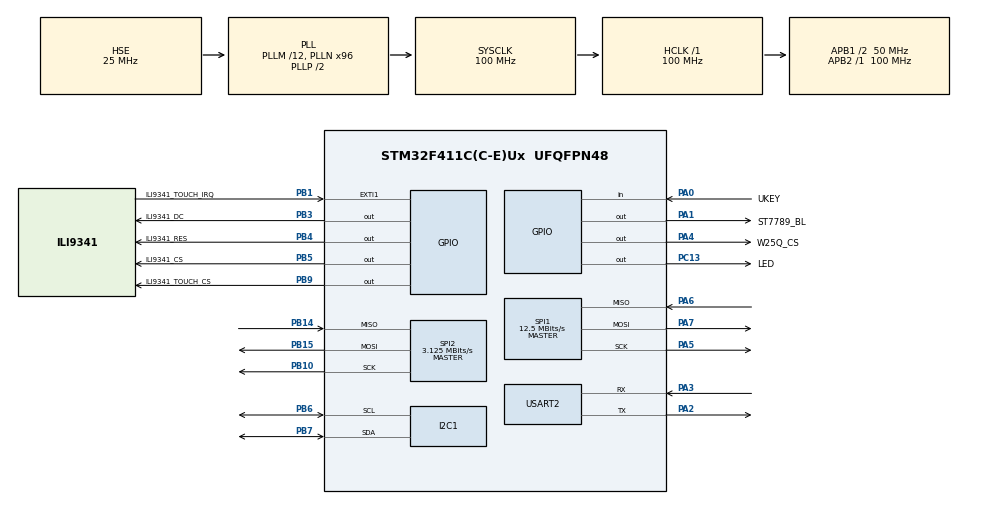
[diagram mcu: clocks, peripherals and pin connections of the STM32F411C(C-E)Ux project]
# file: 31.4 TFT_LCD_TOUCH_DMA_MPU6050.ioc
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Dma.Request0=SPI1_TX
Dma.SPI1_TX.0.Direction=DMA_MEMORY_TO_PERIPH
Dma.SPI1_TX.0.FIFOMode=DMA_FIFOMODE_DISABLE
Dma.SPI1_TX.0.Instance=DMA2_Stream2
Dma.SPI1_TX.0.MemDataAlignment=DMA_MDATAALIGN_BYTE
Dma.SPI1_TX.0.MemInc=DMA_MINC_ENABLE
Dma.SPI1_TX.0.Mode=DMA_NORMAL
Dma.SPI1_TX.0.PeriphDataAlignment=DMA_PDATAALIGN_BYTE
Dma.SPI1_TX.0.PeriphInc=DMA_PINC_DISABLE
Dma.SPI1_TX.0.Priority=DMA_PRIORITY_MEDIUM
Mcu.Family=STM32F4
Mcu.Name=STM32F411C(C-E)Ux
Mcu.Package=UFQFPN48
NVIC.DMA2_Stream2_IRQn=true\:0\:0\:false\:false\:true\:false\:true\:true
NVIC.EXTI1_IRQn=true\:0\:0\:false\:false\:true\:true\:true\:true
NVIC.PriorityGroup=NVIC_PRIORITYGROUP_4
NVIC.SPI1_IRQn=true\:0\:0\:false\:false\:true\:true\:true\:true
NVIC.SPI2_IRQn=true\:0\:0\:false\:false\:true\:true\:true\:true
NVIC.TIM1_UP_TIM10_IRQn=true\:15\:0\:false\:false\:true\:false\:true\:true
NVIC.TIM2_IRQn=true\:1\:0\:true\:false\:true\:true\:true\:true
NVIC.TimeBase=TIM1_UP_TIM10_IRQn
NVIC.TimeBaseIP=TIM10
PA0-WKUP.GPIO_Label=UKEY
PA0-WKUP.GPIO_PuPd=GPIO_PULLUP
PA0-WKUP.Signal=GPIO_Input
PA1.GPIO_Label=ST7789_BL
PA1.Signal=GPIO_Output
PA13.Mode=Serial_Wire
PA13.Signal=SYS_JTMS-SWDIO
PA14.Mode=Serial_Wire
PA14.Signal=SYS_JTCK-SWCLK
PA2.Mode=Asynchronous
PA2.Signal=USART2_TX
PA3.Mode=Asynchronous
PA3.Signal=USART2_RX
PA4.GPIO_Label=W25Q_CS
PA4.Signal=GPIO_Output
PA5.Mode=Full_Duplex_Master
PA5.Signal=SPI1_SCK
PA6.Mode=Full_Duplex_Master
PA6.Signal=SPI1_MISO
PA7.Mode=Full_Duplex_Master
PA7.Signal=SPI1_MOSI
PB1.GPIO_Label=ILI9341_TOUCH_IRQ
PB1.GPIO_ModeDefaultEXTI=GPIO_MODE_IT_FALLING
PB1.GPIO_PuPd=GPIO_PULLUP
PB1.Signal=GPXTI1
PB10.Mode=Full_Duplex_Master
PB10.Signal=SPI2_SCK
PB14.Mode=Full_Duplex_Master
PB14.Signal=SPI2_MISO
PB15.Mode=Full_Duplex_Master
PB15.Signal=SPI2_MOSI
PB3.GPIO_Label=ILI9341_DC
PB3.Signal=GPIO_Output
PB4.GPIO_Label=ILI9341_RES
PB4.Signal=GPIO_Output
PB5.GPIO_Label=ILI9341_CS
PB5.Signal=GPIO_Output
PB6.Mode=I2C
PB6.Signal=I2C1_SCL
PB7.Mode=I2C
PB7.Signal=I2C1_SDA
PB9.GPIO_Label=ILI9341_TOUCH_CS
PB9.Signal=GPIO_Output
PC13-ANTI_TAMP.GPIO_Label=LED
PC13-ANTI_TAMP.Signal=GPIO_Output
PC14-OSC32_IN.Mode=LSE-External-Oscillator
PC14-OSC32_IN.Signal=RCC_OSC32_IN
PC15-OSC32_OUT.Mode=LSE-External-Oscillator
PC15-OSC32_OUT.Signal=RCC_OSC32_OUT
PH0\ -\ OSC_IN.Mode=HSE-External-Oscillator
PH0\ -\ OSC_IN.Signal=RCC_OSC_IN
PH1\ -\ OSC_OUT.Mode=HSE-External-Oscillator
PH1\ -\ OSC_OUT.Signal=RCC_OSC_OUT
ProjectManager.HeapSize=0x400
ProjectManager.StackSize=0x800
ProjectManager.TargetToolchain=STM32CubeIDE
RCC.48MHZClocksFreq_Value=50000000
RCC.AHBFreq_Value=100000000
RCC.APB1CLKDivider=RCC_HCLK_DIV2
RCC.APB1Freq_Value=50000000
RCC.APB1TimFreq_Value=100000000
RCC.APB2Freq_Value=100000000
RCC.APB2TimFreq_Value=100000000
RCC.CortexFreq_Value=100000000
RCC.HCLKFreq_Value=100000000
RCC.HSE_VALUE=25000000
RCC.HSI_VALUE=16000000
RCC.PLLM=12
RCC.PLLN=96
RCC.PLLSourceVirtual=RCC_PLLSOURCE_HSE
RCC.RCC_RTC_Clock_Source=RCC_RTCCLKSOURCE_LSE
RCC.RCC_RTC_Clock_SourceVirtual=RCC_RTCCLKSOURCE_LSE
RCC.SYSCLKFreq_VALUE=100000000
RCC.SYSCLKSource=RCC_SYSCLKSOURCE_PLLCLK
RCC.VCOOutputFreq_Value=200000000
SPI1.BaudRatePrescaler=SPI_BAUDRATEPRESCALER_8
SPI1.CalculateBaudRate=12.5 MBits/s
SPI1.Direction=SPI_DIRECTION_2LINES
SPI1.Mode=SPI_MODE_MASTER
SPI1.VirtualType=VM_MASTER
SPI2.BaudRatePrescaler=SPI_BAUDRATEPRESCALER_16
SPI2.CalculateBaudRate=3.125 MBits/s
SPI2.Direction=SPI_DIRECTION_2LINES
SPI2.Mode=SPI_MODE_MASTER
SPI2.VirtualType=VM_MASTER
TIM2.Period=379
TIM2.Prescaler=8399
USART2.VirtualMode=VM_ASYNC
VP_CRC_VS_CRC.Mode=CRC_Activate
VP_SYS_VS_tim10.Mode=TIM10
VP_TIM2_VS_ClockSourceINT.Mode=Internal
board=custom

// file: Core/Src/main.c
/* USER CODE BEGIN Header */
/**
  ******************************************************************************
  * @file           : main.c
  * @brief          : Main program body
  ******************************************************************************
  * @attention
  *
  * Copyright (c) 2024 STMicroelectronics.
  * All rights reserved.
  *
  * This software is licensed under terms that can be found in the LICENSE file
  * in the root directory of this software component.
  * If no LICENSE file comes with this software, it is provided AS-IS.
  *
  ******************************************************************************
  */
/* USER CODE END Header */
#include "main.h"

/* USER CODE BEGIN Includes */
#include "display_driver.h"
#include "mpu6000.h"
#include "arcade_collection.h"
#include "single_button.h"
#include "w25qxx.h"
/* USER CODE END Includes */

/* USER CODE BEGIN PD */
#define BUTTON_PIN UKEY_Pin
#define BUTTON_PORT UKEY_GPIO_Port
/* USER CODE END PD */

CRC_HandleTypeDef hcrc;
I2C_HandleTypeDef hi2c1;
SPI_HandleTypeDef hspi1;
SPI_HandleTypeDef hspi2;
DMA_HandleTypeDef hdma_spi1_tx;
TIM_HandleTypeDef htim2;
UART_HandleTypeDef huart2;

/* USER CODE BEGIN PV */
ArcadeCollection arcade;
SingleButton ukey_button;
static volatile uint8_t arcade_tick_pending;
/* USER CODE END PV */

void SystemClock_Config(void);
static void MX_GPIO_Init(void);
static void MX_DMA_Init(void);
static void MX_TIM2_Init(void);
static void MX_SPI1_Init(void);
static void MX_CRC_Init(void);
static void MX_SPI2_Init(void);
static void MX_USART2_UART_Init(void);
static void MX_I2C1_Init(void);
/* USER CODE BEGIN PFP */
void init(void);
static uint32_t Arcade_CreateSeed(const MPU6000_Data_t *data);
static void Arcade_ProcessTick(void);
static void Arcade_ProcessButton(void);
/* USER CODE END PFP */

/* USER CODE BEGIN 0 */
static uint32_t Arcade_CreateSeed(const MPU6000_Data_t *data) {
    uint32_t seed = HAL_GetTick() * 0x9E3779B9U;

    seed ^= ((uint32_t)(uint16_t)data->accel_x << 16);
    seed ^= (uint16_t)data->accel_y;
    seed ^= ((uint32_t)(uint16_t)data->accel_z << 1);
    seed ^= ((uint32_t)(uint16_t)data->gyro_x << 11);
    seed ^= ((uint32_t)(uint16_t)data->gyro_y << 21);
    seed ^= ((uint32_t)(uint16_t)data->gyro_z << 5);
    return seed;
}

static void Arcade_ProcessTick(void) {
    MPU6000_Data_t mpu_data;
    HAL_StatusTypeDef mpu_status;

    mpu_status = MPU6000_ReadData(&mpu_data);
    ArcadeCollection_Update(&arcade,
                            &mpu_data,
                            mpu_status);
}

static void Arcade_ProcessButton(void) {
    uint8_t pressed =
        (HAL_GPIO_ReadPin(BUTTON_PORT, BUTTON_PIN) == GPIO_PIN_RESET);
    SingleButtonEvent event =
        SingleButton_Update(&ukey_button, pressed, HAL_GetTick());

    if (event == SINGLE_BUTTON_EVENT_SHORT_PRESS) {
        ArcadeCollection_NextPage(&arcade);
        arcade_tick_pending = 0U;
    } else if (event == SINGLE_BUTTON_EVENT_LONG_PRESS) {
        ArcadeCollection_RestartActive(&arcade);
        arcade_tick_pending = 0U;
    }
}

void init(void) {
    MPU6000_Data_t seed_data;

    DISPLAY_Unselect();
    DISPLAY_TouchUnselect();
    W25Qxx_Unselect();
    DISPLAY_Init();
    MPU6000_Init();
    MPU6000_ReadData(&seed_data);

    SingleButton_Init(
        &ukey_button,
        (HAL_GPIO_ReadPin(BUTTON_PORT, BUTTON_PIN) == GPIO_PIN_RESET),
        HAL_GetTick());
    ArcadeCollection_Init(&arcade, Arcade_CreateSeed(&seed_data));

    arcade_tick_pending = 0U;
    MX_TIM2_Init();
    HAL_TIM_Base_Start_IT(&htim2);
}
/* USER CODE END 0 */

int main(void) {

  /* MCU Configuration--------------------------------------------------------*/
  /* Reset of all peripherals, Initializes the Flash interface and the Systick. */
  HAL_Init();

  /* Configure the system clock */
  SystemClock_Config();

  /* Initialize all configured peripherals */
  MX_GPIO_Init();
  MX_DMA_Init();
  MX_SPI1_Init();
  MX_CRC_Init();
  MX_SPI2_Init();
  MX_USART2_UART_Init();
  MX_I2C1_Init();
  /* USER CODE BEGIN 2 */
  init();
  /* USER CODE END 2 */

  /* Infinite loop */
  /* USER CODE BEGIN WHILE */
  while (1) {
    Arcade_ProcessButton();

    if (arcade_tick_pending != 0U) {
      uint32_t primask = __get_PRIMASK();

      __disable_irq();
      arcade_tick_pending = 0U;
      if (primask == 0U) {
        __enable_irq();
      }

      Arcade_ProcessTick();
    }
    /* USER CODE END WHILE */

  }
}

void SystemClock_Config(void) {
  RCC_OscInitTypeDef RCC_OscInitStruct = {0};
  RCC_ClkInitTypeDef RCC_ClkInitStruct = {0};

  /** Configure the main internal regulator output voltage
  */
  __HAL_RCC_PWR_CLK_ENABLE();
  __HAL_PWR_VOLTAGESCALING_CONFIG(PWR_REGULATOR_VOLTAGE_SCALE1);

  /** Initializes the RCC Oscillators according to the specified parameters
  * in the RCC_OscInitTypeDef structure.
  */
  RCC_OscInitStruct.OscillatorType = RCC_OSCILLATORTYPE_HSE;
  RCC_OscInitStruct.HSEState = RCC_HSE_ON;
  RCC_OscInitStruct.PLL.PLLState = RCC_PLL_ON;
  RCC_OscInitStruct.PLL.PLLSource = RCC_PLLSOURCE_HSE;
  RCC_OscInitStruct.PLL.PLLM = 12;
  RCC_OscInitStruct.PLL.PLLN = 96;
  RCC_OscInitStruct.PLL.PLLP = RCC_PLLP_DIV2;
  RCC_OscInitStruct.PLL.PLLQ = 4;
  if (HAL_RCC_OscConfig(&RCC_OscInitStruct) != HAL_OK) {
    Error_Handler();
  }

  /** Initializes the CPU, AHB and APB buses clocks
  */
  RCC_ClkInitStruct.ClockType = RCC_CLOCKTYPE_HCLK|RCC_CLOCKTYPE_SYSCLK
                              |RCC_CLOCKTYPE_PCLK1|RCC_CLOCKTYPE_PCLK2;
  RCC_ClkInitStruct.SYSCLKSource = RCC_SYSCLKSOURCE_PLLCLK;
  RCC_ClkInitStruct.AHBCLKDivider = RCC_SYSCLK_DIV1;
  RCC_ClkInitStruct.APB1CLKDivider = RCC_HCLK_DIV2;
  RCC_ClkInitStruct.APB2CLKDivider = RCC_HCLK_DIV1;

  if (HAL_RCC_ClockConfig(&RCC_ClkInitStruct, FLASH_LATENCY_3) != HAL_OK) {
    Error_Handler();
  }
}

static void MX_CRC_Init(void) {

  hcrc.Instance = CRC;
  if (HAL_CRC_Init(&hcrc) != HAL_OK) {
    Error_Handler();
  }
}

static void MX_I2C1_Init(void) {

  hi2c1.Instance = I2C1;
  hi2c1.Init.ClockSpeed = 100000;
  hi2c1.Init.DutyCycle = I2C_DUTYCYCLE_2;
  hi2c1.Init.OwnAddress1 = 0;
  hi2c1.Init.AddressingMode = I2C_ADDRESSINGMODE_7BIT;
  hi2c1.Init.DualAddressMode = I2C_DUALADDRESS_DISABLE;
  hi2c1.Init.OwnAddress2 = 0;
  hi2c1.Init.GeneralCallMode = I2C_GENERALCALL_DISABLE;
  hi2c1.Init.NoStretchMode = I2C_NOSTRETCH_DISABLE;
  if (HAL_I2C_Init(&hi2c1) != HAL_OK) {
    Error_Handler();
  }
}

static void MX_SPI1_Init(void) {

  /* SPI1 parameter configuration*/
  hspi1.Instance = SPI1;
  hspi1.Init.Mode = SPI_MODE_MASTER;
  hspi1.Init.Direction = SPI_DIRECTION_2LINES;
  hspi1.Init.DataSize = SPI_DATASIZE_8BIT;
  hspi1.Init.CLKPolarity = SPI_POLARITY_LOW;
  hspi1.Init.CLKPhase = SPI_PHASE_1EDGE;
  hspi1.Init.NSS = SPI_NSS_SOFT;
  hspi1.Init.BaudRatePrescaler = SPI_BAUDRATEPRESCALER_8;
  hspi1.Init.FirstBit = SPI_FIRSTBIT_MSB;
  hspi1.Init.TIMode = SPI_TIMODE_DISABLE;
  hspi1.Init.CRCCalculation = SPI_CRCCALCULATION_DISABLE;
  hspi1.Init.CRCPolynomial = 10;
  if (HAL_SPI_Init(&hspi1) != HAL_OK) {
    Error_Handler();
  }
}

static void MX_SPI2_Init(void) {

  /* SPI2 parameter configuration*/
  hspi2.Instance = SPI2;
  hspi2.Init.Mode = SPI_MODE_MASTER;
  hspi2.Init.Direction = SPI_DIRECTION_2LINES;
  hspi2.Init.DataSize = SPI_DATASIZE_8BIT;
  hspi2.Init.CLKPolarity = SPI_POLARITY_LOW;
  hspi2.Init.CLKPhase = SPI_PHASE_1EDGE;
  hspi2.Init.NSS = SPI_NSS_SOFT;
  hspi2.Init.BaudRatePrescaler = SPI_BAUDRATEPRESCALER_16;
  hspi2.Init.FirstBit = SPI_FIRSTBIT_MSB;
  hspi2.Init.TIMode = SPI_TIMODE_DISABLE;
  hspi2.Init.CRCCalculation = SPI_CRCCALCULATION_DISABLE;
  hspi2.Init.CRCPolynomial = 10;
  if (HAL_SPI_Init(&hspi2) != HAL_OK) {
    Error_Handler();
  }
}

static void MX_TIM2_Init(void) {

  TIM_ClockConfigTypeDef sClockSourceConfig = {0};
  TIM_MasterConfigTypeDef sMasterConfig = {0};

  htim2.Instance = TIM2;
  htim2.Init.Prescaler = 8399;
  htim2.Init.CounterMode = TIM_COUNTERMODE_UP;
  htim2.Init.Period = 380; // 30 Гц (~33 мс)
  htim2.Init.ClockDivision = TIM_CLOCKDIVISION_DIV1;
  htim2.Init.AutoReloadPreload = TIM_AUTORELOAD_PRELOAD_DISABLE;
  if (HAL_TIM_Base_Init(&htim2) != HAL_OK) {
    Error_Handler();
  }
  sClockSourceConfig.ClockSource = TIM_CLOCKSOURCE_INTERNAL;
  if (HAL_TIM_ConfigClockSource(&htim2, &sClockSourceConfig) != HAL_OK) {
    Error_Handler();
  }
  sMasterConfig.MasterOutputTrigger = TIM_TRGO_RESET;
  sMasterConfig.MasterSlaveMode = TIM_MASTERSLAVEMODE_DISABLE;
  if (HAL_TIMEx_MasterConfigSynchronization(&htim2, &sMasterConfig) != HAL_OK) {
    Error_Handler();
  }
  /* USER CODE BEGIN TIM2_Init 2 */
  HAL_NVIC_SetPriority(TIM2_IRQn, 1, 0);
  HAL_NVIC_EnableIRQ(TIM2_IRQn);
  /* USER CODE END TIM2_Init 2 */
}

static void MX_USART2_UART_Init(void) {

  huart2.Instance = USART2;
  huart2.Init.BaudRate = 115200;
  huart2.Init.WordLength = UART_WORDLENGTH_8B;
  huart2.Init.StopBits = UART_STOPBITS_1;
  huart2.Init.Parity = UART_PARITY_NONE;
  huart2.Init.Mode = UART_MODE_TX_RX;
  huart2.Init.HwFlowCtl = UART_HWCONTROL_NONE;
  huart2.Init.OverSampling = UART_OVERSAMPLING_16;
  if (HAL_UART_Init(&huart2) != HAL_OK) {
    Error_Handler();
  }
}

static void MX_DMA_Init(void) {
  /* DMA controller clock enable */
  __HAL_RCC_DMA2_CLK_ENABLE();

  /* DMA interrupt init */
  /* DMA2_Stream2_IRQn interrupt configuration */
  HAL_NVIC_SetPriority(DMA2_Stream2_IRQn, 0, 0);
  HAL_NVIC_EnableIRQ(DMA2_Stream2_IRQn);
}

static void MX_GPIO_Init(void) {
  GPIO_InitTypeDef GPIO_InitStruct = {0};
  /* USER CODE BEGIN MX_GPIO_Init_1 */
  __HAL_RCC_GPIOA_CLK_ENABLE();
  HAL_GPIO_WritePin(W25Q_CS_GPIO_Port,
                    W25Q_CS_Pin,
                    GPIO_PIN_SET);
  /* USER CODE END MX_GPIO_Init_1 */

  /* GPIO Ports Clock Enable */
  __HAL_RCC_GPIOC_CLK_ENABLE();
  __HAL_RCC_GPIOH_CLK_ENABLE();
  __HAL_RCC_GPIOA_CLK_ENABLE();
  __HAL_RCC_GPIOB_CLK_ENABLE();

  /*Configure GPIO pin Output Level */
  HAL_GPIO_WritePin(LED_GPIO_Port, LED_Pin, GPIO_PIN_RESET);

  /*Configure GPIO pin Output Level */
  HAL_GPIO_WritePin(ST7789_BL_GPIO_Port, ST7789_BL_Pin, ST7789_BL_OFF_STATE);

  /*Configure GPIO pin Output Level */
  HAL_GPIO_WritePin(DISPLAY_DC_GPIO_Port, DISPLAY_DC_Pin, GPIO_PIN_RESET);
  HAL_GPIO_WritePin(DISPLAY_RES_GPIO_Port, DISPLAY_RES_Pin, GPIO_PIN_RESET);

  /*Configure GPIO pin Output Level */
  HAL_GPIO_WritePin(DISPLAY_CS_GPIO_Port, DISPLAY_CS_Pin, GPIO_PIN_SET);
  HAL_GPIO_WritePin(DISPLAY_TOUCH_CS_GPIO_Port, DISPLAY_TOUCH_CS_Pin, GPIO_PIN_SET);

  /*Configure GPIO pin : LED_Pin */
  GPIO_InitStruct.Pin = LED_Pin;
  GPIO_InitStruct.Mode = GPIO_MODE_OUTPUT_PP;
  GPIO_InitStruct.Pull = GPIO_NOPULL;
  GPIO_InitStruct.Speed = GPIO_SPEED_FREQ_LOW;
  HAL_GPIO_Init(LED_GPIO_Port, &GPIO_InitStruct);

  /*Configure GPIO pin : UKEY_Pin */
  GPIO_InitStruct.Pin = UKEY_Pin;
  GPIO_InitStruct.Mode = GPIO_MODE_INPUT;
  GPIO_InitStruct.Pull = GPIO_PULLUP;
  HAL_GPIO_Init(UKEY_GPIO_Port, &GPIO_InitStruct);

  /*Configure GPIO pin : ST7789_BL_Pin */
  GPIO_InitStruct.Pin = ST7789_BL_Pin;
  GPIO_InitStruct.Mode = GPIO_MODE_OUTPUT_PP;
  GPIO_InitStruct.Pull = GPIO_NOPULL;
  GPIO_InitStruct.Speed = GPIO_SPEED_FREQ_LOW;
  HAL_GPIO_Init(ST7789_BL_GPIO_Port, &GPIO_InitStruct);

  /*Configure GPIO pin : DISPLAY_TOUCH_IRQ_Pin */
  GPIO_InitStruct.Pin = DISPLAY_TOUCH_IRQ_Pin;
  GPIO_InitStruct.Mode = GPIO_MODE_IT_FALLING;
  GPIO_InitStruct.Pull = GPIO_PULLUP;
  HAL_GPIO_Init(DISPLAY_TOUCH_IRQ_GPIO_Port, &GPIO_InitStruct);

  /*Configure GPIO pins : DISPLAY_DC_Pin DISPLAY_RES_Pin DISPLAY_CS_Pin DISPLAY_TOUCH_CS_Pin */
  GPIO_InitStruct.Mode = GPIO_MODE_OUTPUT_PP;
  GPIO_InitStruct.Pull = GPIO_NOPULL;
  GPIO_InitStruct.Speed = GPIO_SPEED_FREQ_LOW;
  GPIO_InitStruct.Pin = DISPLAY_DC_Pin;
  HAL_GPIO_Init(DISPLAY_DC_GPIO_Port, &GPIO_InitStruct);
  GPIO_InitStruct.Pin = DISPLAY_RES_Pin;
  HAL_GPIO_Init(DISPLAY_RES_GPIO_Port, &GPIO_InitStruct);
  GPIO_InitStruct.Pin = DISPLAY_CS_Pin;
  HAL_GPIO_Init(DISPLAY_CS_GPIO_Port, &GPIO_InitStruct);
  GPIO_InitStruct.Pin = DISPLAY_TOUCH_CS_Pin;
  HAL_GPIO_Init(DISPLAY_TOUCH_CS_GPIO_Port, &GPIO_InitStruct);

  /* EXTI interrupt init*/
  HAL_NVIC_SetPriority(EXTI1_IRQn, 0, 0);
  HAL_NVIC_EnableIRQ(EXTI1_IRQn);

  /* USER CODE BEGIN MX_GPIO_Init_2 */
  GPIO_InitStruct.Pin = W25Q_CS_Pin;
  GPIO_InitStruct.Mode = GPIO_MODE_OUTPUT_PP;
  GPIO_InitStruct.Pull = GPIO_NOPULL;
  GPIO_InitStruct.Speed = GPIO_SPEED_FREQ_VERY_HIGH;
  HAL_GPIO_Init(W25Q_CS_GPIO_Port, &GPIO_InitStruct);

  HAL_GPIO_WritePin(DISPLAY_CS_GPIO_Port, DISPLAY_CS_Pin, GPIO_PIN_SET);
  HAL_GPIO_WritePin(DISPLAY_TOUCH_CS_GPIO_Port,
                    DISPLAY_TOUCH_CS_Pin,
                    GPIO_PIN_SET);
  HAL_GPIO_WritePin(W25Q_CS_GPIO_Port, W25Q_CS_Pin, GPIO_PIN_SET);
  HAL_GPIO_WritePin(DISPLAY_RES_GPIO_Port, DISPLAY_RES_Pin, GPIO_PIN_SET);
  HAL_GPIO_WritePin(ST7789_BL_GPIO_Port, ST7789_BL_Pin, ST7789_BL_OFF_STATE);
  /* USER CODE END MX_GPIO_Init_2 */
}

/* USER CODE BEGIN 4 */
/**
  * @brief  Period elapsed callback in non-blocking mode
  * @param  htim : TIM handle
  * @retval None
  */
void HAL_TIM_PeriodElapsedCallback(TIM_HandleTypeDef *htim) {
	/* USER CODE BEGIN Callback 0 */
	if (htim->Instance == TIM2) {
		arcade_tick_pending = 1U;
	}
	/* USER CODE END Callback 0 */

  if (htim->Instance == TIM10) {
    HAL_IncTick();
  }
  /* USER CODE BEGIN Callback 1 */
  /* USER CODE END Callback 1 */
}
/* USER CODE END 4 */

void Error_Handler(void) {
  __disable_irq();
  while (1) {
  }
}
